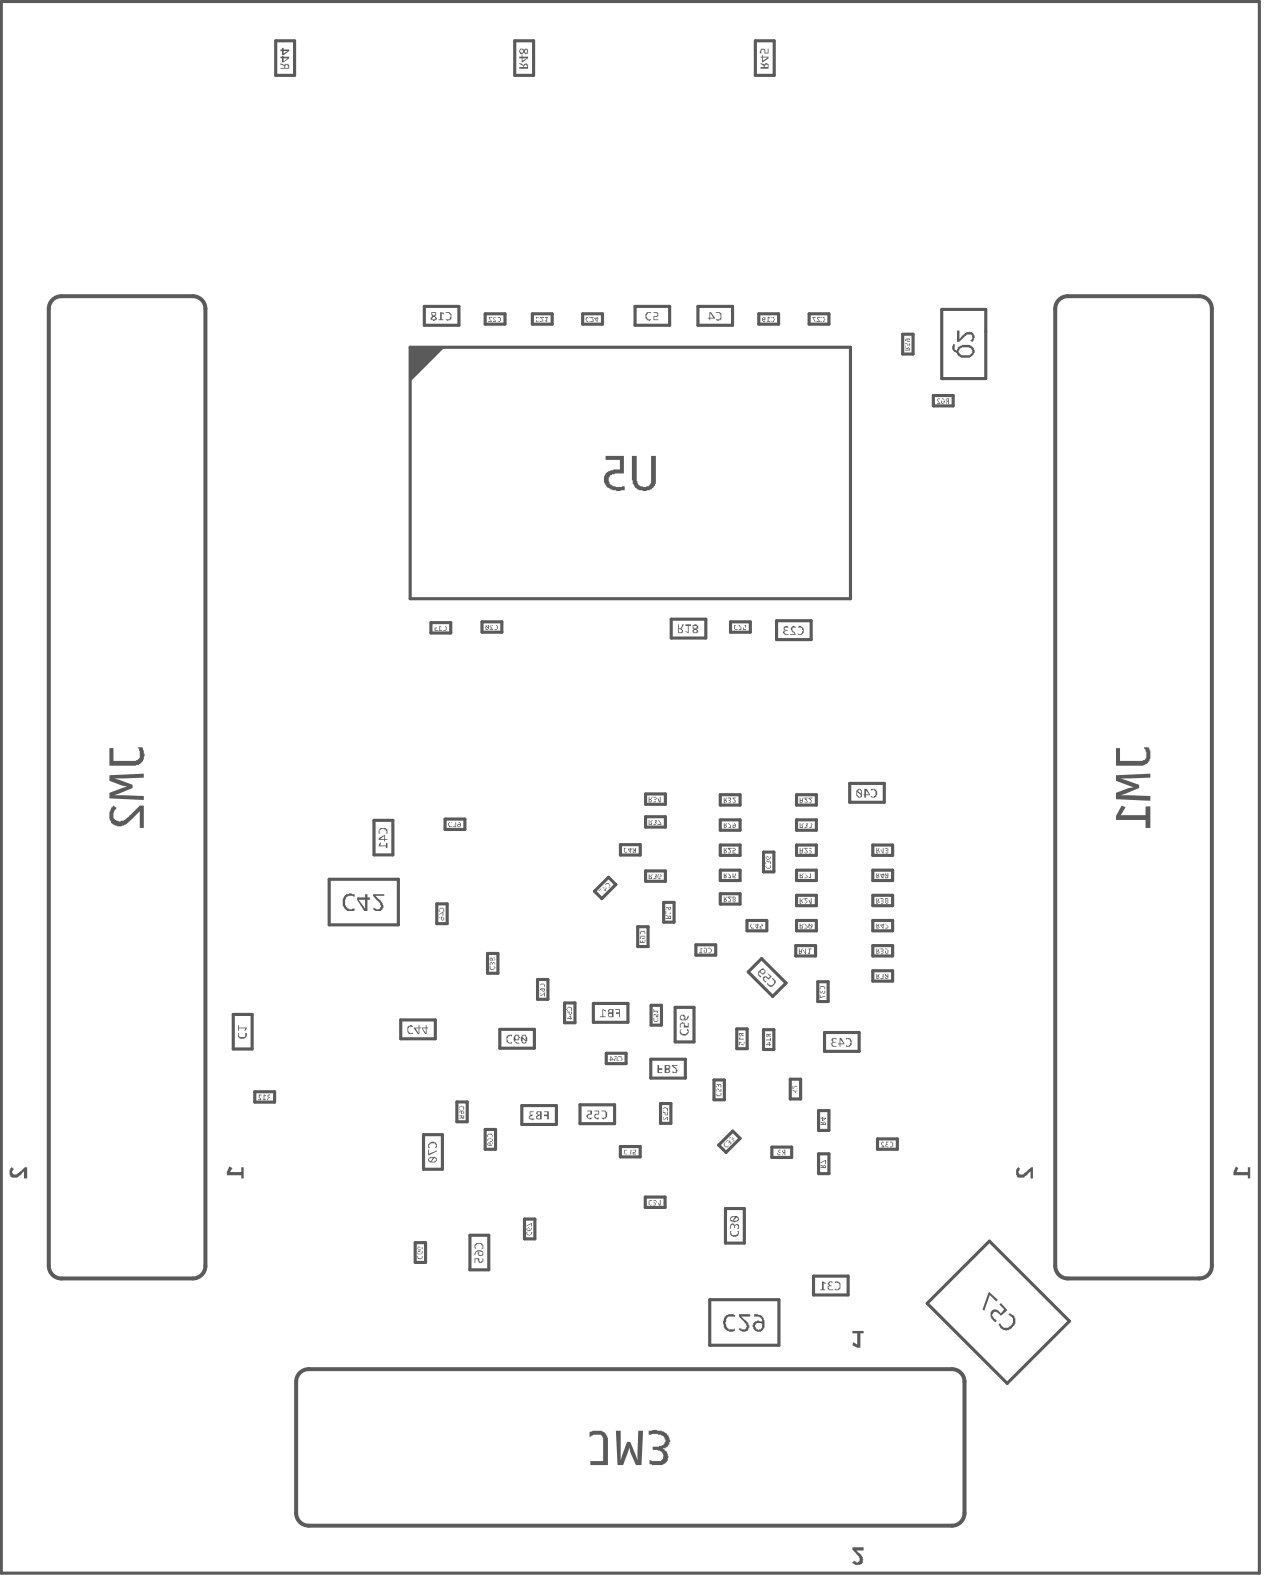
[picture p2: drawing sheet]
<svg xmlns="http://www.w3.org/2000/svg" width="134mm" height="167mm" viewBox="0 0 134 167" stroke-linecap="round" stroke-linejoin="round" font-family="sans-serif">
<path d="M43.4 36.7h3.6l-3.6 3.7z" fill="#5a5a5a"/>
<g fill="none" stroke="#5a5a5a" stroke-width=".33">
<path d="M29.2 4.3h2v3.7h-2zM54.4 4.3h2v3.7h-2zM79.9 4.3h2v3.7h-2zM43.4 36.7h46.6v26.7h-46.6zM44.9 32.4h3.6v2h-3.6zM51.3 33.2h2.1v1.1h-2.1zM56.3 33.2h2.1v1.1h-2.1zM61.6 33.2h2.1v1.1h-2.1zM67.2 32.4h3.6v2h-3.6zM73.8 32.4h3.7v2h-3.7zM80.3 33.2h2.1v1.1h-2.1zM85.6 33.2h2.1v1.1h-2.1z"/>
<path d="M95.5 35.4h1.1v2.1h-1.1zM99.6 32.7h4.7v7.4h-4.7zM98.7 41.9h2.1v1h-2.1zM45.6 65.9h2.1v1.1h-2.1zM51 65.8h2.1v1.1h-2.1zM71 65.5h3.7v2h-3.7zM77.3 65.8h2.1v1.1h-2.1zM82.1 65.7h3.7v2h-3.7zM34.8 93h7.3v4.9h-7.3zM39.6 86.8h2v3.7h-2zM46.2 95.6h1.1v2.1h-1.1zM47.1 86.7h2.1v1.1h-2.1z"/>
<path d="M62.9 94.3l1.5-1.5 .7 .8-1.4 1.5zM65.6 89.4h2.1v1.1h-2.1zM67.5 98.1h1.1v2.1h-1.1zM68.3 84h2.1v1.1h-2.1zM68.3 86.4h2.1v1.1h-2.1zM68.3 92.2h2.1v1.1h-2.1zM70.2 95.5h1.1v2.1h-1.1zM73.6 100h2.1v1.1h-2.1zM76.2 89.4h2.1v1.1h-2.1zM76.2 92.1h2.1v1.1h-2.1zM76.2 86.8h2.1v1h-2.1zM76.2 84.1h2.1v1.1h-2.1z"/>
<path d="M76.2 94.6h2.1v1.1h-2.1zM79 97.4h2.1v1.1h-2.1zM80.8 90.2h1.1v2.1h-1.1zM84.3 89.4h2.1v1.1h-2.1zM84.3 97.4h2.1v1.1h-2.1zM84.3 92.1h2.1v1.1h-2.1zM84.3 94.7h2.1v1.1h-2.1zM84.3 84.1h2.1v1.1h-2.1zM84.3 86.8h2.1v1h-2.1zM89.9 82.9h3.6v2h-3.6zM92.3 89.4h2.1v1.1h-2.1zM92.3 92.1h2.1v1.1h-2.1z"/>
<path d="M92.3 94.7h2.1v1.1h-2.1zM92.3 97.4h2.1v1.1h-2.1zM24.7 107.3h2v3.7h-2zM27 115.5h2v1.1h-2zM42.4 107.9h3.6v2h-3.6zM48.3 116.6h1.1v2.1h-1.1zM51.3 119.5h1.1v2.1h-1.1zM51.6 100.9h1.1v2.1h-1.1zM52.9 108.9h3.6v2h-3.6zM55.2 117h3.7v2h-3.7zM56.9 103.6h1.1v2.1h-1.1zM59.7 106.1h1.1v2.1h-1.1z"/>
<path d="M61.4 116.9h3.6v2h-3.6zM62.8 106.2h3.6v2h-3.6zM64.1 111.4h2.1v1.1h-2.1zM68.8 112.1h3.7v2h-3.7zM68.9 106.4h1.1v2.1h-1.1zM69.9 116.8h1.1v2.1h-1.1zM71.4 106.6h2v3.6h-2zM75.5 114.3h1.1v2.1h-1.1zM77.9 108.9h1.1v2.1h-1.1zM80.6 101.4l2.5 2.6-1.4 1.4-2.6-2.6zM80.8 109h1.1v2h-1.1zM83.6 114.2h1.1v2.1h-1.1z"/>
<path d="M84.2 100.1h2.1v1.1h-2.1zM86.5 103.9h1.1v2.1h-1.1zM86.6 117.5h1.1v2.1h-1.1zM87.2 109.3h3.7v1.9h-3.7zM92.3 100.1h2.1v1.1h-2.1zM92.3 102.7h2.1v1.1h-2.1zM43.9 131.5h1.1v2.1h-1.1zM44.8 120.1h2v3.6h-2zM49.7 130.7h2v3.7h-2zM55.5 129h1.1v2.1h-1.1zM65.6 121.3h2.1v1.1h-2.1zM68.3 126.7h2.1v1.1h-2.1z"/>
<path d="M75.1 137.5h7.3v4.8h-7.3zM76 121.2l1.5-1.5 .8 .8-1.5 1.4zM76.7 127.9h2v3.6h-2zM81.6 121.4h2.1v1.1h-2.1zM86.1 135h3.6v2h-3.6zM86.6 122.1h1.1v2.1h-1.1zM92.8 120.5h2.1v1.1h-2.1zM98.1 137.9l6.6-6.6 8.4 8.5-6.6 6.6z"/>
</g>
<path d="M5.2 32.7v101.2M6.5 31.3h13.9M21.7 32.7v101.2M111.6 32.7v101.2M113 31.3h13.9M128.2 32.7v101.2M6.5 135.3h13.9M113 135.3h13.9M31.3 146.2v13.9M32.7 144.9h68M102 146.2v13.9M32.7 161.4h68" fill="none" stroke="#5a5a5a" stroke-width=".42"/>
<g fill="#5a5a5a">
<path d="M105.6 140.2l.2-.2 .2 .3a.66 .66 0 0 0 1.1-.3v-.1a.45 .45 0 0 0-.2-.6v-.1l-.3-.1 .2-.1a.86 .86 0 0 1 .6 .7 .86 .86 0 0 1-.5 .9l-.2 .1a.86 .86 0 0 1-1-.4z"/>
<path d="M104.9 138.7a.53 .53 0 0 1 .8 .1l.2 .2 .3-.5-.5-.5 .2-.1 .7 .7-.7 .6-.4-.2a.26 .26 0 0 0-.2-.2 .26 .26 0 0 0-.3 .3v.3l.5 .3-.2 .2-.1-.1a.89 .89 0 0 1-.4-1z"/>
<path d="M104.6 136.7l.9 .8-.1 .2-.7-.7-.6 1.7-.2-.2z"/>
<path d="M36.4 94.8l.2-.2h.2l.1-.1 .6 .1v.3h-.2v-.1a.63 .63 0 0 0-.8 .7v.3h.1a.3 .3 0 0 0 .3 .3v.1h.3l.1-.1h.2v.2a.85 .85 0 0 1-1.2-.7v-.5z"/>
<path d="M39.5 94.6h1.1v.2h-.9l.4 .4a.86 .86 0 0 1 .4 1h-.1a.43 .43 0 0 1-.6 .2l-.3-.2 .1-.1a.34 .34 0 0 0 .5 .1 .34 .34 0 0 0 .1-.5v-.2l-.7-.7z"/>
<path d="M76.6 139.3l.2-.1a.63 .63 0 0 1 .7-.1h.2v.3l-.2-.1a.51 .51 0 0 0-.7 .6h-.1l.1 .3a.57 .57 0 0 0 .9 .4v.2l-.2 .1a.55 .55 0 0 1-.6-.2l-.3-.2v-.3l-.1-.1z"/>
<path d="M78.2 139.1h1.1v.2h-.9l.4 .4a.79 .79 0 0 1 .4 1h-.1a.48 .48 0 0 1-.7 .1l-.2-.1v-.2a.52 .52 0 0 0 .7 .1v-.2h.1l-.1-.3-.7-.8z"/>
<path d="M80.4 5.2h.1a.24 .24 0 0 1 .3 0 .24 .24 0 0 1 .2 .2v.2h.2v-.4h.1v.5h-.4v-.3a.18 .18 0 0 0-.3-.2 .18 .18 0 0 0-.1 .3v.2l-.1-.1z"/>
<path d="M72.5 66.1h.6v.1h-.3v.8l-.3-.2v-.1l.3 .2v-.7h-.3z"/>
<path d="M57.5 117.6h.6v.8h-.2v-.3h-.4v-.2h.4v-.2h-.4z"/>
<path d="M56 117.6h.4v.1h-.3v.2h.3v.1l-.4 .2a.38 .38 0 0 0 .5 .2h-.1a.34 .34 0 0 1-.5-.2l.2-.2-.1-.2h-.1h.1z"/>
<path d="M69.5 112.7h.2v.3h.4v.2h-.4v.3h.4h-.6z"/>
<path d="M71.1 112.7h.6v.1h-.5l.5 .4-.1 .3h-.4h-.1l.1-.1v.1a.19 .19 0 0 0 .3-.1 .19 .19 0 0 0-.1-.3z"/>
<path d="M65.1 106.8h.5v.8h-.1v-.3h-.3v-.2h.3v-.2h-.4z"/>
<path d="M63.7 106.8l.4 .2-.3-.1v.6h.3v.1h-.6v-.1h.2z"/>
<path d="M45.3 121.1h.1a.44 .44 0 0 1 .6-.3 .44 .44 0 0 1 .1 .7v-.2a.35 .35 0 0 0-.5-.3l-.2 .1 .1 .4-.2-.1z"/>
<path d="M45.3 121.7h.1v.4l.8-.4v.1l-.9 .4z"/>
<path d="M50.2 131.7h.1a.44 .44 0 0 1 .6-.2l.1 .1a.38 .38 0 0 1 .1 .5h-.1a.24 .24 0 0 0 0-.2 .24 .24 0 0 0-.1-.2v-.1a.38 .38 0 0 0-.5 .2h-.1l.1 .2-.1 .1-.1-.1z"/>
<path d="M50.2 133.1h.5v.4l.1 .1 .2-.2v-.3a.24 .24 0 0 1 .1 .3 .24 .24 0 0 1-.1 .2h-.3l-.1-.2h-.1v-.2h-.2v.4h-.1z"/>
<path d="M53.7 109.6l.5-.1v.2l-.2-.1-.3 .1v.1v.3v.1a.24 .24 0 0 0 .2 .1 .24 .24 0 0 0 .3-.1v.2h-.2a.34 .34 0 0 1-.4-.4v-.3z"/>
<path d="M81.1 104.1l.1-.1a.36 .36 0 0 0 .5 .2 .36 .36 0 0 0 .2-.5l-.3-.1 .2-.1 .1 .2a.27 .27 0 0 1 .2 .2 .27 .27 0 0 1-.2 .3h-.1a.31 .31 0 0 1-.3 .2 .31 .31 0 0 1-.3-.2z"/>
<path d="M80.7 103.4l.1-.1h.3l.2 .2 .2-.2-.3-.3 .4 .3-.3 .4-.2-.2a.18 .18 0 0 0-.2 0 .18 .18 0 0 0 0 .2l.1 .1v.2l-.3-.3z"/>
<path d="M71.9 109l.2-.1a.3 .3 0 0 0-.1 .3 .3 .3 0 0 0 .2 .2h.2a.3 .3 0 0 0 .4-.3h-.1v-.2a.31 .31 0 0 1 .1 .3 .31 .31 0 0 1-.2 .3v.1h-.3a.42 .42 0 0 1-.4-.5z"/>
<path d="M72 108.2h.2v-.1l.2 .1v.3l.1 .1h.3v-.4v.5h-.5v-.4h-.2l-.1 .1v.3h-.1z"/>
<path d="M63.6 117.5a.38 .38 0 0 1 .5 .2l.1 .1a.45 .45 0 0 1-.2 .6h-.1h-.3v-.1h.3a.43 .43 0 0 0 .2-.6l-.1-.1h-.4v.1z"/>
<path d="M62.9 117.5h.5v.4h-.3a.18 .18 0 0 0-.1 .3 .18 .18 0 0 0 .2 .1h.2v.1h-.1h-.3a.26 .26 0 0 1-.1-.3 .26 .26 0 0 1 .2-.3h.2v-.2h-.4z"/>
<path d="M62.1 117.5h.5v.4h-.3l-.1 .1v.3h.4v.1h-.2h-.2l-.2-.2a.32 .32 0 0 1 .4-.4v-.2h-.3z"/>
<path d="M43.2 108.6h.1a.24 .24 0 0 1 .2-.1 .24 .24 0 0 1 .2 .1 .34 .34 0 0 0-.4 .1 .34 .34 0 0 0-.1 .3 .32 .32 0 0 0 .4 .3l.1-.1v.2h-.1a.39 .39 0 0 1-.4-.1 .39 .39 0 0 1-.1-.4v-.3z"/>
<path d="M89.5 109.8a.44 .44 0 0 1 .5 .1 .44 .44 0 0 1 .1 .5 .32 .32 0 0 1-.4 .4h-.2v-.2a.34 .34 0 0 0 .5-.3 .34 .34 0 0 0-.5-.3z"/>
<path d="M88 109.9l.1-.1h.4v.2l-.1-.1h-.3a.22 .22 0 0 0 0 .3 .22 .22 0 0 0 .3 0v.1h-.3v.3v.1h.4v.1a.34 .34 0 0 1-.5-.3l-.1-.1 .2-.2h-.1z"/>
<path d="M40.1 87.7l.3-.1a.38 .38 0 0 1 .5 .2h.1v.4h-.2a.34 .34 0 0 0-.1-.5 .34 .34 0 0 0-.5 .2h-.1v.2l.1 .1h-.1z"/>
<path d="M40.2 89.1l.1 .1-.1 .3h.6v-.3h.2v.5h-.2v-.2h-.7z"/>
<path d="M92.1 83.6l.1-.1h.2a.48 .48 0 0 1 .4 .3 .48 .48 0 0 1-.2 .5 .3 .3 0 0 1-.5-.1l.2 .1a.35 .35 0 0 0 .3-.5l-.2-.2h-.1h-.2z"/>
<path d="M88.3 135.7l.2-.1a.34 .34 0 0 1 .4 .4v.2a.32 .32 0 0 1-.4 .3h-.2v-.1a.24 .24 0 0 0 .2 0 .24 .24 0 0 0 .2-.1h.1a.48 .48 0 0 0-.3-.6v.1h-.2z"/>
<path d="M87.5 135.8h.1a.24 .24 0 0 1 .2-.2 .24 .24 0 0 1 .3 .1v.1l-.2-.1a.18 .18 0 0 0-.2 .2 .18 .18 0 0 0 .3 .1v.1h-.3a.25 .25 0 0 0 .1 .3 .25 .25 0 0 0 .3 0v.1a.39 .39 0 0 1-.4 0 .39 .39 0 0 1-.2-.4l.2-.1h-.1z"/>
<path d="M87 135.6l.4 .2h-.1h-.2v.6h.2v.1h-.5v-.1h.2z"/>
<path d="M77.2 130.3h.2l-.1 .2 .2 .2a.38 .38 0 0 0 .5-.2h.1l-.1-.2h.2v.2a.48 .48 0 0 1-.4 .4 .48 .48 0 0 1-.5-.2l-.1-.1z"/>
<path d="M77.3 129.5l.3-.1 .1 .3a.23 .23 0 0 1 .3-.2 .23 .23 0 0 1 .2 .3v.2h-.2l.1-.1-.1-.3-.3 .1v.2v-.1a.18 .18 0 0 0-.3-.2 .18 .18 0 0 0-.1 .2v.2h-.1v-.4z"/>
<path d="M84.4 66.3a.3 .3 0 0 1 .3-.1 .3 .3 0 0 1 .2 .3l.1 .1a.38 .38 0 0 1-.2 .5v.1h-.4v-.2a.24 .24 0 0 0 .3 .1 .24 .24 0 0 0 .1-.3 .3 .3 0 0 0 0-.3 .3 .3 0 0 0-.3-.1z"/>
<path d="M83.7 66.4a.22 .22 0 0 1 .3-.2 .22 .22 0 0 1 .2 .3l-.1-.1a.19 .19 0 0 0-.3 .1 .19 .19 0 0 0 .1 .2l.3 .5h-.6v-.1h.5l-.4-.3z"/>
<path d="M82.9 66.3h.1a.24 .24 0 0 1 .2-.1 .24 .24 0 0 1 .2 .2h-.3l-.1 .1 .1 .2h.2h-.2a.18 .18 0 0 0-.1 .3 .18 .18 0 0 0 .2 .1h.2v.1a.38 .38 0 0 1-.5-.2h-.1v-.2l.3-.1h-.2z"/>
<path d="M47.2 33a.38 .38 0 0 1 .5 .2v.1a.55 .55 0 0 1-.1 .6l-.3 .1-.1-.2a.34 .34 0 0 0 .3 0 .34 .34 0 0 0 .2-.3 .32 .32 0 0 0-.5-.4v.1z"/>
<path d="M46.6 33l.4 .1-.1 .2-.2-.2v.7h.2v.1h-.5v-.1h.2z"/>
<path d="M68.3 33.2l.1-.2h.5v.2a.24 .24 0 0 0-.3-.1 .24 .24 0 0 0-.2 .3v.3l.1 .1h.4l-.2 .2-.1-.1a.32 .32 0 0 1-.3-.4z"/>
<path d="M69.1 33a.34 .34 0 0 1 .5 .3l-.1 .2h-.3v.3h.4v.1h-.5v-.4h.3a.18 .18 0 0 0 .1-.3 .18 .18 0 0 0-.2-.1h-.2z"/>
<path d="M75.7 33a.44 .44 0 0 1 .5 .1 .44 .44 0 0 1 .1 .5l-.1 .3-.2 .1-.3-.1v-.1a.34 .34 0 0 0 .4 0 .34 .34 0 0 0 .1-.3 .35 .35 0 0 0-.5-.4v.1z"/>
<path d="M25.2 109.3h.2a.24 .24 0 0 0-.1 .3 .24 .24 0 0 0 .2 .1 .3 .3 0 0 0 .4 0 .3 .3 0 0 0 0-.4h.2v.2a.46 .46 0 0 1-.6 .4 .32 .32 0 0 1-.3-.4z"/>
<path d="M25.2 108.5h.1v.2h.8v.1l-.2 .3v-.3h-.6v.3h-.1z"/>
<path d="M93.6 89.7h.3l.1 .1v.2h-.1l.1 .2-.1 .1-.3-.1h.3v-.1h-.2v-.1h.2v-.2h-.3z"/>
<path d="M93.6 97.7h.4h-.3l.1 .2a.18 .18 0 0 1 .2 .2 .18 .18 0 0 1-.3 .2l-.1-.1h.3v-.2z"/>
<path d="M85.5 100.4h.4h-.2v.6l-.3-.1 .1-.1 .1 .1v-.5z"/>
<path d="M93.1 100.4h.3h.1v.2h-.1l.1 .3-.1 .1h-.2v-.1h.2v-.2h-.2v-.1l.3-.1-.1-.1h-.3z"/>
<path d="M93.1 95h.3l.1 .1v.2h-.1l.1 .2-.1 .1h-.2v-.1h.2v-.1h-.2v-.1l.3-.1-.1-.1h-.3z"/>
<path d="M69.1 86.8h.4v.2h-.1l.1 .2-.1 .1h-.3v-.1h.3l-.2-.2 .2-.2z"/>
<path d="M69.6 86.8h.1l.3 .5h-.5v-.1h.4z"/>
<path d="M69.1 92.5h.4v.3h-.1l.1 .1-.1 .1h-.3v-.1h.3l-.2-.1 .2-.2z"/>
<path d="M69.1 84.3h.2a.17 .17 0 0 1 .2 .2 .17 .17 0 0 1-.2 .1l.2 .1-.2 .2h-.2v-.1l.3-.1v-.1h-.2h.2v-.2h-.3z"/>
<path d="M85.1 87.1h.3v.3h-.1l.1 .1-.1 .1h-.2v-.1h.2l-.1-.1 .1-.2z"/>
<path d="M85.6 87.1h.3v.1l-.1 .2h.1v.2h-.3v-.1h.2v-.1h-.2l.3-.1-.1-.2z"/>
<path d="M77 84.4h.3v.2h-.1l.1 .3-.1 .1h-.1v-.1h.1v-.2h-.1v-.1h.2l-.1-.1h-.2z"/>
<path d="M77.5 84.4h.3v.1h-.2l.2 .3a.17 .17 0 0 1-.1 .2 .17 .17 0 0 1-.2-.2l.2 .1v-.2z"/>
<path d="M93.1 103.1h.4v.2h-.1h.1a.19 .19 0 0 1-.1 .3 .19 .19 0 0 1-.3-.1h.3v-.2h-.2l.2-.1v-.1z"/>
<path d="M77 87.1h.4h-.3l.2 .3v.2h-.2l-.1-.1h.2v-.1z"/>
<path d="M77 94.9h.4v.1h-.3h.1a.24 .24 0 0 1 .1 .3 .24 .24 0 0 1-.2 .2l-.1-.1 .1-.1v.1h.1v-.3z"/>
<path d="M77 92.4h.4h-.3l.2 .3v.2h-.2l-.1-.1h.2v-.1z"/>
<path d="M77 89.7h.4v.1h-.2a.33 .33 0 0 1 0 .5l-.2-.1 .1-.1v.1h.1v-.2z"/>
<path d="M77.5 89.7h.2a.18 .18 0 0 1 .1 .2 .18 .18 0 0 1-.2 .2v.1h.2v.1h-.3v-.3h.2v-.2h-.2z"/>
<path d="M85.1 95h.3v.1h-.2l.2 .3-.1 .2-.2-.1h.2v-.1l-.1-.1z"/>
<path d="M85.1 89.7h.3v.1h-.2l.2 .3a.17 .17 0 0 1-.1 .2 .17 .17 0 0 1-.2-.2l.2 .1v-.1z"/>
<path d="M85.6 89.7h.3v.2l-.1 .1 .1 .1-.1 .2h-.2v-.1h.2v-.1h-.2v-.1h.3v-.2h-.3z"/>
<path d="M85.1 84.4h.3v.1h-.2l.1 .1 .1 .2a.17 .17 0 0 1-.1 .2 .17 .17 0 0 1-.2-.2l.2 .1v-.2l-.1-.1z"/>
<path d="M85.5 84.4h.4v.1h-.3l.2 .1a.24 .24 0 0 1 .1 .2 .24 .24 0 0 1-.2 .2l-.2-.1 .1-.1v.1h.2v-.3z"/>
<path d="M85.1 92.4h.3h-.2l.1 .2a.18 .18 0 0 1 .1 .2 .18 .18 0 0 1-.2 .1l-.1-.1h.2v-.1z"/>
<path d="M85.6 92.4h.3h-.1v.5l-.3-.1h.1h.1v-.4z"/>
<path d="M85.1 97.7h.3h-.2l.1 .2a.18 .18 0 0 1 .1 .2 .18 .18 0 0 1-.2 .2l-.1-.1h.2v-.2z"/>
<path d="M70.4 96.4h.1v.2h.5l-.1 .1h-.1l.1-.1h-.4v.1h-.1z"/>
<path d="M78.2 109.7l.1 .1-.1 .1h.5v-.1v.4v-.2h-.5z"/>
<path d="M78.2 110.2h.2l.1 .3h.2v-.3h.1v.2h-.1v.2h-.3v-.3h-.2v.3z"/>
<path d="M81.1 109.8l-.1 .2h.5v-.2v.4v-.1h-.5z"/>
<path d="M27.9 115.8l.2 .1v.1l-.1-.1v.4h.1v.1h-.3l.1-.1z"/>
<path d="M27.4 115.8h.2v.2v-.1h-.1v.3l.1 .2h-.3v-.1h.2l-.1-.1z"/>
<path d="M86.8 123l.6-.3v.5h-.1v-.4l-.5 .3z"/>
<path d="M82.3 121.7h.3h-.2v.2h.2v.1h-.3v.2h.3h-.3h-.1v-.2h.2z"/>
<path d="M83.8 114.9h.1v.2l.2-.2h.2v.3l-.1-.1h.1v-.1h-.2l-.3 .2z"/>
<path d="M51.5 120h.3a.22 .22 0 0 1 .2 0 .22 .22 0 0 1 .1 .3h-.1h.1a.24 .24 0 0 0-.2-.2 .24 .24 0 0 0-.3 0v.2h-.1z"/>
<path d="M48.6 117.1l.3-.1v.1h.2v.3h-.1v-.1a.22 .22 0 0 0-.2-.2 .22 .22 0 0 0-.2 .2l.1 .1h-.1z"/>
<path d="M55.7 130.4h.1a.23 .23 0 0 0 .2 .3 .23 .23 0 0 0 .2-.3h.1v.2l-.3 .1v.1l-.3-.2z"/>
<path d="M55.7 129.7l.6-.3v.4h-.1v-.3l-.5 .3z"/>
<path d="M44.1 133l.2-.1-.1 .1a.24 .24 0 0 0 .2 .1 .24 .24 0 0 0 .2 0v-.2h.1v.2a.38 .38 0 0 1-.5 .1z"/>
<path d="M65.4 111.8h.3v.1a.24 .24 0 0 1 .1 .2 .24 .24 0 0 1-.2 .2h-.2v-.1l.2 .1a.23 .23 0 0 0 .1-.3 .23 .23 0 0 0-.3-.1z"/>
<path d="M67.7 98.6l.2-.1a.22 .22 0 0 1 .3 .1 .22 .22 0 0 1 0 .2h-.1h.1a.24 .24 0 0 0-.2-.2 .24 .24 0 0 0-.2 .1v.1h-.1z"/>
<path d="M67.7 99.5h.1v.2h.1v-.2h.1v.2h.2v-.3h.1l-.1 .4h-.3v-.1v.1h-.2z"/>
<path d="M57.1 104.2h.1a.24 .24 0 0 1 .3-.1 .24 .24 0 0 1 .1 .2l-.1 .1a.19 .19 0 0 0 0-.2 .19 .19 0 0 0-.3 0h-.1v.2h.1h-.1z"/>
<path d="M57.1 105l.1 .1-.1 .2h.3l.2-.3v.4h-.1v-.3l-.1 .2h-.3z"/>
<path d="M74.9 100.3h.1a.32 .32 0 0 1 .3 .4l-.2 .2-.2-.1h.1a.23 .23 0 0 0 .2-.3 .23 .23 0 0 0-.3-.1z"/>
<path d="M74.1 100.3l.2 .1h-.1v.4l.1 .1h-.4v-.1h.2z"/>
<path d="M60 106.6a.31 .31 0 0 1 .4 0 .31 .31 0 0 1 .1 .4h-.1a.23 .23 0 0 0-.1-.4 .23 .23 0 0 0-.3 .3l.1 .1-.2-.1z"/>
<path d="M60 107h.2v.3h.2v-.3h.1v.2a.18 .18 0 0 1-.2 .2 .18 .18 0 0 1-.1-.3h-.2v.3z"/>
<path d="M75.7 115.7h.2h-.1a.24 .24 0 0 0 .2 .2 .24 .24 0 0 0 .2-.1v-.1h.1v.1a.38 .38 0 0 1-.5 .2z"/>
<path d="M75.9 115.1l.2 .1v.2h.1v-.2h.1v.3h-.2l-.1-.3-.3 .3z"/>
<path d="M75.8 114.7h.3v.1v-.1h.1l.1 .1v.3h-.1v-.3h-.1v.2h-.1v-.2h-.2v.3h-.1z"/>
<path d="M70.1 117.3l.1-.1h.3v.1h.1v.3v-.2a.21 .21 0 0 0-.3-.2 .21 .21 0 0 0-.1 .4h-.1z"/>
<path d="M70.1 117.7h.3v.2h.2v-.2v.2l-.2 .1-.1-.2h-.2v.2z"/>
<path d="M70.1 118.2h.1l-.1 .1 .1 .1 .4-.2v.3v-.2l-.4 .2-.1-.1z"/>
<path d="M69.1 107.7h.1v.2h-.1h.1v.2h.3v-.2h.1l-.1-.2a.24 .24 0 0 1 .1 .3 .24 .24 0 0 1-.2 .1h-.3z"/>
<path d="M69.1 107.4l.3-.1 .1 .2v-.2h.1v.3h-.2v-.2h-.2l-.1 .1 .1 .1h-.1z"/>
<path d="M69.1 106.8h.1v.2h.4l-.1 .2v-.1v-.1h-.3l-.1 .1z"/>
<path d="M66 89.7h.3v.1l-.1-.1a.24 .24 0 0 0-.1 .2 .24 .24 0 0 0 .1 .2h.1v.1h-.1a.38 .38 0 0 1-.2-.5z"/>
<path d="M64.1 93.5l.1-.1a.3 .3 0 0 1 .3 .2 .3 .3 0 0 1 0 .3h-.2a.23 .23 0 0 0 .2-.3 .23 .23 0 0 0-.4-.1v.2l-.1-.1z"/>
<path d="M63.3 94.3l.3-.3-.2 .3 .5 .1z"/>
<path d="M46.5 96.1h.1a.24 .24 0 0 1 .2 0 .24 .24 0 0 1 .2 .2v.2l-.1-.1a.19 .19 0 0 0-.1-.3 .19 .19 0 0 0-.2 .1h-.1l.1 .3h-.1l-.1-.1z"/>
<path d="M79.3 97.8l.1-.1h.4v.1l-.2-.1a.23 .23 0 0 0-.2 .4 .23 .23 0 0 0 .4 .1v.1h-.4z"/>
<path d="M80.4 97.7h.2l.1 .1v.2l-.3 .1 .2 .2h-.2v-.3l.2-.1-.1-.2z"/>
<path d="M47.4 87.1l.1-.1h.3v.1a.22 .22 0 0 0-.2 0 .22 .22 0 0 0-.1 .3h.1h.2v.1h-.3z"/>
<path d="M47.9 87h.4v.3h-.1l.1 .2h-.4v-.1h.3l-.2-.1h.2v-.3z"/>
<path d="M51.8 102.2h.1a.23 .23 0 0 0 .1 .4 .23 .23 0 0 0 .3-.3l-.1-.1a.17 .17 0 0 1 .2 .2 .17 .17 0 0 1-.2 .2 .24 .24 0 0 1-.3 0 .24 .24 0 0 1-.1-.2z"/>
<path d="M51.8 101.9l.1-.1h.2v.1l.2-.1 .1 .3h-.1v-.2h-.2v.2v-.2h-.2v.2h-.1z"/>
<path d="M86.8 104.3a.34 .34 0 0 1 .5 .3l-.1 .1a.22 .22 0 0 0-.2-.3 .22 .22 0 0 0-.2 .2l.1 .1h-.2z"/>
<path d="M86.7 104.8h.1v.2h.2v-.2v.3h.2v-.3h.1v.3l-.3 .1v-.2l-.2 .1z"/>
<path d="M86.7 105.3h.1v.2l.5-.2v.1l-.6 .2z"/>
<path d="M81 91.7l.1-.1-.1 .1a.24 .24 0 0 0 .2 .1 .24 .24 0 0 0 .3-.1v-.1v.1a.27 .27 0 0 1-.2 .2 .27 .27 0 0 1-.3-.2z"/>
<path d="M81 91.1l.3 .1 .2-.1v.1v.2v-.2l-.2 .1-.1-.1h-.2v.2z"/>
<path d="M66 121.7h.1h.2h-.1a.27 .27 0 0 0-.1 .2 .27 .27 0 0 0 .1 .3l.1-.1v.1h-.2l-.1-.1z"/>
<path d="M66.5 121.7h.3l-.1 .2h.1v.3h-.3v-.1l.2 .1v-.3h-.2l.3-.1-.1-.1z"/>
<path d="M66.9 121.7h.4v.2l-.3 .1v.1h.3v.1h-.4v-.3h.3v-.2h-.1h-.2z"/>
<path d="M68.6 127.1l.1-.1h.3v.1a.22 .22 0 0 0-.3 .1 .22 .22 0 0 0 .2 .3l.1-.1v.1a.25 .25 0 0 1-.3-.1 .25 .25 0 0 1-.1-.3z"/>
<path d="M69.1 127h.3l.1 .1v.1h-.2l.1 .1-.1 .3h-.2v-.1h.2v-.2h-.2v-.1h.3v-.1h-.3z"/>
<path d="M76.6 121l.2-.1a.21 .21 0 0 0-.2 .3 .21 .21 0 0 0 .4 0l.1-.1v.1a.24 .24 0 0 1-.2 .2 .24 .24 0 0 1-.3-.1v-.1z"/>
<path d="M76.8 120.7a.24 .24 0 0 1 .2-.1 .24 .24 0 0 1 .2 .2l.2 .1-.2 .2 .1-.2-.2 .1 .1-.3-.1-.1-.2 .2z"/>
<path d="M77.2 120.4v-.1h.3l.1 .1-.1 .1h.2v.2l-.2 .1 .2-.2h-.3v-.1h.1l-.1-.2-.2 .2z"/>
<path d="M94.1 120.8h.2a.38 .38 0 0 1 .2 .5l-.1 .1h-.3v-.1h.3v-.4h-.3z"/>
<path d="M93.7 120.8h.3v.1l-.3 .1 .2 .1h-.2v.2h.3v.1l-.4-.1v-.2h.2h-.1z"/>
<path d="M93.2 120.9l.1-.1 .2 .1v.1v-.1h-.2v.2l.2 .3h-.3v-.1h.3l-.3-.2z"/>
<path d="M86.9 33.5h.3v.2a.25 .25 0 0 1 0 .3 .25 .25 0 0 1-.3 0 .21 .21 0 0 0 .3-.1 .21 .21 0 0 0 0-.2 .21 .21 0 0 0-.3-.1z"/>
<path d="M86.4 33.5h.4v.1h-.2v-.1l-.1 .1v.2l.3 .2h-.4h.3l-.3-.2z"/>
<path d="M85.9 33.5h.4v.1h-.3l.3 .4h-.1z"/>
<path d="M77.7 66.1h.3v.1l-.1-.1a.24 .24 0 0 0-.2 .2 .24 .24 0 0 0 .1 .3h.2v.1h-.2a.38 .38 0 0 1-.1-.6z"/>
<path d="M78.1 66.1h.4h-.3l.1 .2a.19 .19 0 0 1 .1 .3 .19 .19 0 0 1-.2 .1l-.1-.1h.2v-.3z"/>
<path d="M78.6 66.1h.3v.3h-.2v.2h.2v.1h-.3v-.3h.2v-.2z"/>
<path d="M62 33.5h.4v.1a.21 .21 0 0 0-.3 .1 .21 .21 0 0 0 0 .2 .21 .21 0 0 0 .3 .1h-.4v-.1h-.1z"/>
<path d="M62.4 33.5h.4v.1h-.3l.3 .2a.19 .19 0 0 1-.1 .2 .19 .19 0 0 1-.3 0h.2h.1v-.2z"/>
<path d="M52.6 33.5h.2a.27 .27 0 0 1 .2 .4 .27 .27 0 0 1-.4 .1h.1h.2v-.4h-.2v-.1l-.1 .1z"/>
<path d="M52.1 33.6l.1-.1h.3v.1l-.1-.1a.17 .17 0 0 0-.2 .2 .17 .17 0 0 0 .2 .2l.1 .1h-.4h.3l-.2-.1z"/>
<path d="M51.7 33.5h.4v.1h-.2v-.1l-.1 .1v.2l.3 .2h-.5h.4l-.3-.2z"/>
<path d="M56.7 33.5h.3v.1a.21 .21 0 0 0-.2 .1 .21 .21 0 0 0 0 .2 .21 .21 0 0 0 .2 .1 .21 .21 0 0 1-.3 0 .21 .21 0 0 1 0-.3z"/>
<path d="M57.1 33.5h.4v.1h-.3l.3 .2a.19 .19 0 0 1-.1 .2 .19 .19 0 0 1-.3 0h.3v-.2z"/>
<path d="M57.6 33.5h.4l-.1 .1v.4h-.3v-.1l.2 .1v-.4h-.2z"/>
<path d="M52.3 66.1v.1a.21 .21 0 0 1 .3 0 .21 .21 0 0 1 0 .3v.2h-.3v-.1a.19 .19 0 0 0 .3-.1 .19 .19 0 0 0-.1-.3v-.1z"/>
<path d="M51.8 66.2l.1-.1h.2v.1v-.1l-.2 .1 .2 .5h-.3v-.1h.3l-.2-.1z"/>
<path d="M81.5 33.5h.4v.2a.25 .25 0 0 1-.1 .3 .25 .25 0 0 1-.3 0 .21 .21 0 0 0 .3-.1 .21 .21 0 0 0 0-.2 .21 .21 0 0 0-.3-.1z"/>
<path d="M81.2 33.5l.3 .1-.1 .1-.1-.1v.4h.2h-.4h.1z"/>
<path d="M46.9 66.2v.1v-.1h.2a.27 .27 0 0 1 .1 .4 .27 .27 0 0 1-.3 .1 .19 .19 0 0 0 .3-.1 .19 .19 0 0 0-.1-.3v-.1z"/>
<path d="M46.5 66.2l.2 .1h-.1v.4h.1h-.3h.1z"/>
<path d="M46 66.2h.2v.3h-.1v.2h.2a.19 .19 0 0 1-.2 0 .19 .19 0 0 1-.1-.2 .19 .19 0 0 1 .2-.1v-.2z"/>
<path d="M90.2 140.8h1.1v.3h-.3v1.5h-.3l-.5-.3v-.3l.5 .3v-1.2h-.5z"/>
<path d="M90.2 163.7h1.1v.4h-.7l.3 .3a.79 .79 0 0 1 .3 1.1l-.4 .1a.55 .55 0 0 1-.6-.2v-.1l.1-.1h.3v.1a.35 .35 0 0 0 .3-.5h-.1v-.1l-.6-.7z"/>
<path d="M62.4 151.6a2.07 2.07 0 0 1 1.4-.1l.3 .1v.3a.55 .55 0 0 1 .2 .6v2.5h-1.9v-.4h1.4v-2.5h-.1a.57 .57 0 0 0-.7-.3h-.2l-.4 .3z"/>
<path d="M65.2 151.4h.5v3.1l.6-1.9h.4l.7 1.9 .1-3.1h.5l-.1 3.6h-.6l-.6-1.3-.1-.5-.7 1.8h-.6z"/>
<path d="M68.6 151.4h.4v-.1h.5v.1a.86 .86 0 0 1 .9 .2 .98 .98 0 0 1 .4 1.2h-.1l-.1 .3-.5 .2h.1l.1 .2a.48 .48 0 0 1 .3 .6h.1l-.1 .3a1 1 0 0 1-1.2 .6l-.7-.1v-.4l.6 .1a.6 .6 0 0 0 .8-.4l.1-.2h-.1v-.2l-.1-.2-.5-.2h-.5v-.3h.7l.1-.1a.43 .43 0 0 0 .5-.4h.1l-.1-.5a.68 .68 0 0 0-.7-.3l-.1-.1-.9 .1z"/>
<path d="M24.3 123.4l.3 .2-.3 .4h1.2v-.5h.3v1.2h-.3v-.3h-1.5v-.4z"/>
<path d="M11.6 79.2h.4v1.3h2.1a.63 .63 0 0 0 .7-.8l-.1-.5-.2-.1h.5l.2 .3v.3h.1l-.1 .5a1.08 1.08 0 0 1-.6 .7l-.2 .1h-2.8z"/>
<path d="M11.6 82l3.6-.1v.4l-3.1 .1 1.9 .6v.4l-1.9 .7 3.1 .1v.4l-3.6-.1v-.6l1.8-.7-.5-.1-1.3-.5z"/>
<path d="M11.7 85.5l.3-.3 .3 .3v.1a.98 .98 0 0 0-.2 1.1l.2 .1a1.26 1.26 0 0 0 1.1-.2l1.4-1.4h.4v2.4h-.4v-1.8l-.9 1a2.07 2.07 0 0 1-1.2 .6h-.3h-.1a.81 .81 0 0 1-.6-.6l-.1-.1v-.8z"/>
<path d="M1.1 123.6l.2-.1 .1 .2v.2h-.1a.35 .35 0 0 0 .5 .4v-.1l.2-.1 .6-.6h.3v1.2h-.4v-.8l-.5 .5a.72 .72 0 0 1-.8 .1l-.2-.1v-.6h.1z"/>
<path d="M130.7 123.4l.3 .2-.2 .4h1.2v-.5h.2v1.2h-.2v-.3h-1.5v-.4z"/>
<path d="M118 79.2h.5v1.3h2.3a.73 .73 0 0 0 .4-1.1l-.2-.3h.5a1.8 1.8 0 0 1-.1 1.7l-.5 .2h-2.9z"/>
<path d="M118 82l3.7-.1v.4l-3.1 .1 1.9 .6v.4l-1.9 .7 3.1 .1v.5l-3.7-.1v-.7l1.4-.5 .5-.1-1.9-.7z"/>
<path d="M118.6 85.2l.5 .2-.5 .9h2.6v-1h.5v2.3h-.5v-.8h-3.2v-.5z"/>
<path d="M107.7 123.5l.2 .2a.34 .34 0 0 0 0 .6h.3l.1-.2 .3-.1 .5-.5h.2v1.2h-.3v-.8l-.3 .5h-.3a.44 .44 0 0 1-.6 .2h-.1a.97 .97 0 0 1 0-1.1z"/>
<path d="M66.8 48.2h.5v2.7h.1a.44 .44 0 0 0 .5 .5 .64 .64 0 0 0 1-.5v-2.7h.5v2.5a1.01 1.01 0 0 1-1 1.2v.1h-.4l-.1-.1a.89 .89 0 0 1-.9-.7h-.1v-.3l-.1-.1z"/>
<path d="M64.1 48.2h1.9v1.9h-.9l-.1 .1a.59 .59 0 0 0-.6 .3 .59 .59 0 0 0 .1 .6 1.13 1.13 0 0 0 1.1 .4l.5-.1v.5h-.4v.1a2.08 2.08 0 0 1-1.6-.6 1.01 1.01 0 0 1 .4-1.6l.4-.1h.7v-1h-1.5z"/>
<path d="M95.7 36.3h.3l.1 .3h.1v-.3v.3h-.2l-.1-.3v.1h-.2v.2h.1l-.1 .1z"/>
<path d="M101.2 35h.3v.9l.6-.7 .4-.1h.2a.3 .3 0 0 1 .3 .4h.1v.2l-.2 .5-.2-.1v-.1a.38 .38 0 0 0 .1-.5l-.1-.1a.38 .38 0 0 0-.5 .2l-.7 .6h-.3z"/>
<path d="M99.1 42.2h.1h.3h-.3v.2h.1l.2 .3h-.4h.3l-.3-.3z"/>
<path d="M37.9 95.2h.7v.9zM37.8 95v.2l.7 1.2h.4v-1.2h.2v-.2h-.2v-.4h-.3v.4z"/>
<path d="M79.9 140.1l.2-.1a.34 .34 0 0 1 .5 .2v.3l-.4 .2-.3-.3zM79.8 139.1v.2a.63 .63 0 0 1 .8 .5v.1v-.1h-.2a.4 .4 0 0 0-.5 .1l-.1 .1a.33 .33 0 0 0-.1 .5v.1a.58 .58 0 0 0 1 .1h.1a1.68 1.68 0 0 0-.1-1.3l-.3-.3z"/>
<path d="M55.5 6.8l.3 .1v.2h-.4zM54.9 6.7v.1l.4 .1v.2h-.4v.2h1v-.5l-.2-.1-.3 .1-.1 .1v-.1z"/>
<path d="M55.3 6.2h.5l-.5 .2zM54.9 6v.2h.3v.4l.7-.4v-.2h-.6v-.2h-.1v.2z"/>
<path d="M55.5 5.3l.2-.1 .1 .1v.3h-.3zM55 5.3l.3-.1v.3l-.2 .1zM55 5.2a.36 .36 0 0 0 .2 .5l.1-.1 .2 .1a.25 .25 0 0 0 .3-.1 .25 .25 0 0 0 .1-.3 .22 .22 0 0 0-.3-.1 .22 .22 0 0 0-.2 .1l-.1-.1z"/>
<path d="M81 6.8h.2v.3h-.3zM80.4 6.7v.1l.4 .1v.2h-.4v.2h.9v-.4a.22 .22 0 0 0-.2-.2 .22 .22 0 0 0-.2 .2l-.1-.1z"/>
<path d="M80.7 6.1h.5l-.5 .3zM80.4 6v.1h.2v.5l.7-.4v-.2h-.6v-.2h-.1v.2z"/>
<path d="M30.2 6.9l.2-.1 .1 .4h-.3zM29.7 6.7v.1l.4 .2v.2h-.4v.1h.9v-.3a.26 .26 0 0 0-.2-.2 .26 .26 0 0 0-.3 .1v-.1z"/>
<path d="M30 6.2h.4l-.4 .3zM29.7 6v.2h.1v.4h.2l.6-.4v-.2h-.6v-.1z"/>
<path d="M30 5.4h.4l-.4 .3zM29.7 5.2v.2h.1v.4h.2l.6-.4v-.2h-.6v-.1h-.2v.1z"/>
<path d="M71.8 66.6h.2l.2 .2-.1 .1h-.3zM71.7 66.1v.9h.4a.22 .22 0 0 0 .2-.2 .22 .22 0 0 0-.2-.2l.2-.5h-.1l-.2 .4h-.2v-.4z"/>
<path d="M73.3 66.7h.1h.3v.2h-.3zM73.3 66.2h.4v.3h-.3zM73.3 66.1v.4l.1 .1a.23 .23 0 0 0-.1 .3 .23 .23 0 0 0 .3 .1l.3-.1v-.2l-.2-.1a.22 .22 0 0 0 .2-.2 .22 .22 0 0 0-.2-.3z"/>
<path d="M56.9 117.7h.2v.2h-.2zM56.8 118.2l.3-.2v.4h-.2zM56.8 117.6l-.1 .2 .2 .2a.23 .23 0 0 0-.2 .3 .23 .23 0 0 0 .3 .1h.3v-.8z"/>
<path d="M70.5 113.2h.2v.3h-.2zM70.5 112.8h.2l.1 .1-.1 .1h-.2zM70.3 112.7v.8h.3a.22 .22 0 0 0 .2 0 .22 .22 0 0 0 0-.3l-.1-.1a.23 .23 0 0 0 .2-.3 .23 .23 0 0 0-.3-.1z"/>
<path d="M64.4 107l.1-.1h.2v.2h-.2zM64.4 107.3h.3v.2h-.3zM64.3 106.9v.2l.2 .1h-.1a.24 .24 0 0 0-.1 .3 .24 .24 0 0 0 .3 .1h.3v-.8h-.5z"/>
<path d="M45.4 122.6l.4-.1-.3 .4-.1-.2zM46 122.5v.1h.1v.1l-.1 .2h-.4zM45.3 122.6a.34 .34 0 0 0 .4 .4h.2a.32 .32 0 0 0 .3-.4 .87 .87 0 0 0-.7-.2z"/>
<path d="M50.7 132.4l.3 .1v.2v.1h-.3v-.2h-.1zM50.3 132.5l-.1 .3 .2-.2v-.1l.2-.1-.1 .2a.3 .3 0 0 0 .5 .3 .3 .3 0 0 0 0-.5l-.1-.1a.55 .55 0 0 0-.6 .2z"/>
<path d="M54.5 109.8a.21 .21 0 0 1 .4 0 .21 .21 0 0 1-.4 0zM54.4 109.6v.1a.57 .57 0 0 0 .3 .7h.2v-.1l-.4-.1v-.2l.1 .1h.2l.1-.3h.1l-.1-.1a.3 .3 0 0 0-.5-.1z"/>
<path d="M55.3 109.9l.3 .3a.18 .18 0 0 1-.2 .1 .18 .18 0 0 1-.1-.2zM55.3 109.7l.1-.1a.38 .38 0 0 1 .2 .5zM55.2 109.6l-.1 .1v.5h.1a.26 .26 0 0 0 .3 .2 .26 .26 0 0 0 .2-.2h.1v-.5h-.1a.3 .3 0 0 0-.5-.1z"/>
<path d="M80.4 102.7h.1a.19 .19 0 0 1 .3-.1 .19 .19 0 0 1 .1 .3l-.1 .1h-.3zM80.2 102.8a.38 .38 0 0 0 .2 .5v.1l.1-.1-.1-.1a.24 .24 0 0 1-.1-.2 .24 .24 0 0 1 .1-.2l.1 .3a.26 .26 0 0 0 .3 0 .26 .26 0 0 0 .2-.3 .26 .26 0 0 0-.2-.3 .26 .26 0 0 0-.3 .1z"/>
<path d="M72 107.5h.2a.21 .21 0 0 1 .2 .2 .21 .21 0 0 1-.3 .2 .21 .21 0 0 1-.1-.4zM71.9 107.5v.2a.34 .34 0 0 0 .5 .3l.4-.1v-.4l-.1 .3h-.2v.1h-.1l.1-.1-.1-.4h-.3z"/>
<path d="M43.9 108.8h.4v.5zM43.8 108.7l.4 .7h.2v-.6h.1v-.1h-.1v-.2h-.1v.2z"/>
<path d="M44.7 108.8h.3v.5zM44.6 108.7l.4 .7h.1v-.6h.2v-.1h-.2v-.2h-.1v.2z"/>
<path d="M88.9 110l.3 .4h-.3zM88.8 109.8v.6h-.2v.1h.2v.3h.1v-.3h.4v-.1l-.3-.6z"/>
<path d="M40.2 88.8l.4-.3v.3zM40.1 88.7v.2h.5v.1h.1v-.1h.3v-.1h-.3v-.4z"/>
<path d="M91.6 83.6l.3 .5h-.3zM91.4 83.5v.6h-.1h.1v.3h.2v-.3h.4l-.3-.6z"/>
<path d="M90.8 83.6a.25 .25 0 0 1 .3 .1 .25 .25 0 0 1 0 .3zM90.7 83.8l.4 .3-.1 .2a.32 .32 0 0 1-.3-.4zM90.6 83.6v.2a.38 .38 0 0 0 .2 .5 .24 .24 0 0 0 .2 .1 .24 .24 0 0 0 .2-.3 .45 .45 0 0 0-.3-.6h-.1z"/>
<path d="M77.6 129.2l.4-.4a.25 .25 0 0 1 0 .3 .25 .25 0 0 1-.3 .1zM77.3 128.9l.2-.2h.2l-.2 .5-.2-.1zM77.3 128.7v.1a.24 .24 0 0 0-.1 .3 .24 .24 0 0 0 .3 .2h.1a.39 .39 0 0 0 .4-.1 .39 .39 0 0 0 .2-.4h-.1a.44 .44 0 0 0-.6-.1z"/>
<path d="M45.7 33.1h.4v.1a.18 .18 0 0 1-.3 .2 .18 .18 0 0 1-.1-.3zM45.7 33.6l.3-.1 .1 .3h-.4zM45.6 33v.4l.2 .1-.3 .1v.2l.3 .1v.1l.3-.1a.17 .17 0 0 0 .1-.2 .17 .17 0 0 0-.1-.2h-.1a.24 .24 0 0 0 .1-.2 .24 .24 0 0 0 0-.3z"/>
<path d="M75.1 33.1l.4 .5h-.4zM75 33v.6h-.1v.1h.1v.2h.1v-.2h.5l-.4-.7z"/>
<path d="M92.8 90.1h.2v.1h-.2zM92.7 89.7v.6h.2v-.1h.1v-.1l-.1-.1h.1v-.3l-.1 .3h-.1v-.3z"/>
<path d="M93.2 89.9h.2v.3zM93.1 89.9l.3 .4h.1v-.4v-.2h-.1v.2z"/>
<path d="M92.8 98l.2 .2h-.2zM92.7 97.7v.6h.3v-.2l-.1-.1h.1v-.3l-.1 .2z"/>
<path d="M93.2 97.9h.2v.3zM93.1 97.8l.3 .5h.1v-.4v-.1v-.1l-.1 .1z"/>
<path d="M84.6 100.7h.2v.2h-.2zM84.5 100.4v.6h.3v-.1v-.3l.1-.2h-.1v.2h-.2v-.2z"/>
<path d="M85 100.5h.2v.4zM84.9 100.5l.3 .5h.1v-.5v-.1h-.1v.1z"/>
<path d="M92.8 92.7l.2 .1h-.2zM92.7 92.4v.5h.3v-.1l-.1-.1h.1v-.3l-.2 .3v-.3z"/>
<path d="M93.2 92.6h.2v.2zM93.1 92.5l.2 .4h.2v-.3v-.1v-.1l-.1 .1z"/>
<path d="M93.6 92.6l.3 .2h-.3zM93.7 92.4l.2 .1v.2zM93.6 92.4l-.1 .3 .1 .1a.21 .21 0 0 0 .3 .1 .21 .21 0 0 0 .1-.3v-.2z"/>
<path d="M92.8 100.7h.2v.1l-.2 .1zM92.7 100.4v.6h.2v-.1h.1v-.2l-.1-.1h.1v-.2l-.1 .2h-.1v-.2z"/>
<path d="M93.7 100.6h.2v.3h-.2zM93.6 100.4h.3v.2h-.3v.2a.18 .18 0 0 0 .2 .1 .18 .18 0 0 0 .2-.2v-.2l-.2-.1z"/>
<path d="M92.8 95.4h.2v.1h-.2zM92.7 95v.6h.2v-.1h.1v-.1l-.1-.1h.1v-.3l-.1 .3h-.1v-.3z"/>
<path d="M93.7 95.4h.2v.1h-.2zM93.7 95.1h.2v.2h-.2zM93.6 95v.3h.1l-.1 .2a.18 .18 0 0 0 .2 .1 .18 .18 0 0 0 .2-.2h-.1l.1-.3-.1-.1z"/>
<path d="M68.7 87h.2v.2h-.2zM68.6 86.8v.5h.4v-.3l-.1-.1 .1-.1-.2 .2h-.1v-.2z"/>
<path d="M68.7 92.8h.2v.1h-.2zM68.6 92.5v.5h.4v-.2l-.1-.1 .1-.2-.1 .2h-.2v-.2z"/>
<path d="M69.7 92.5l.2 .1-.1 .2h-.2zM69.5 92.6v.2l.2 .2h.2v-.1h-.2l-.1-.1h.2l.2-.1a.24 .24 0 0 0-.2-.2 .24 .24 0 0 0-.3 .1z"/>
<path d="M68.7 84.6h.2v.2h-.2zM68.6 84.3v.6h.3l.1-.1-.1-.2 .1-.3-.2 .3h-.1v-.3z"/>
<path d="M69.6 84.5h.2v.3zM69.5 84.5l.2 .4h.2v-.4h.1h-.1v-.2h-.1v.2z"/>
<path d="M84.7 87.4h.1v.1h-.1zM84.6 87.1v.5h.3v-.2l-.1-.1 .2-.2-.2 .3h-.1v-.3z"/>
<path d="M76.6 84.7h.2v.2h-.2zM76.6 84.4v.6h.1v-.1h.2v-.2l-.2-.1h.1l.1-.2h-.1l-.1 .2h-.1v-.2z"/>
<path d="M92.8 103.3l.2 .2h-.2zM92.7 103.1v.5h.3v-.2l-.1-.1h.1v-.2l-.1 .1z"/>
<path d="M93.6 103.2l.3 .3-.3-.1zM93.7 103.1h.2v.2zM93.6 103.1l-.1 .2h.1v.3h.2a.38 .38 0 0 0 .2-.5z"/>
<path d="M76.6 87.4h.2v.1h-.2zM76.6 87.1v.5h.2l.1-.2h-.2h.1l.1-.3-.2 .2z"/>
<path d="M77.6 87.4h.1v.1h-.1zM77.5 87.1h.2v.2a.19 .19 0 0 0-.2 .1 .19 .19 0 0 0 .1 .2h.1a.27 .27 0 0 0 .1-.3 .27 .27 0 0 0-.3-.2z"/>
<path d="M76.6 95.2h.2v.2h-.2zM76.6 94.9v.6h.1l.2-.1v-.2l-.2-.1h.1l.1-.2h-.1l-.1 .2h-.1v-.2z"/>
<path d="M77.6 95.2h.1v.2h-.1zM77.6 95h.1v.1h-.1zM77.5 94.9v.2h.1l-.1 .2a.18 .18 0 0 0 .2 .2 .18 .18 0 0 0 .1-.3h-.1l.1-.1-.1-.2z"/>
<path d="M76.6 92.7l.2 .1h-.2zM76.6 92.4v.5h.2l.1-.1-.2-.1h.1l.1-.3-.3 .3v-.3z"/>
<path d="M77.6 92.4h.1v.3h-.1zM77.5 92.4a.34 .34 0 0 0 .2 .5l.1-.1h-.2v-.1v.1h.1l.1-.1v-.3z"/>
<path d="M76.6 90.1h.2v.1h-.2zM76.6 89.7v.6h.1l.2-.1v-.1l-.2-.1h.1l.1-.3h-.1l-.1 .3h-.1v-.3z"/>
<path d="M84.7 95.4h.1v.1h-.1zM84.6 95v.6h.2v-.1h.1l-.1-.3 .2-.2-.2 .3h-.1v-.3z"/>
<path d="M85.6 95.2h.2v.3zM85.5 95.2l.2 .4h.2v-.4v-.2h-.1v.2z"/>
<path d="M84.7 90.1h.1v.1h-.1zM84.6 89.7v.6h.2l.1-.1v-.2h-.1h.1l.1-.3h-.1l-.1 .3h-.1v-.3z"/>
<path d="M84.7 84.7h.1v.2h-.1zM84.6 84.4v.6h.2l.1-.1v-.3h-.1h.1l.1-.2h-.1l-.1 .2h-.1v-.2z"/>
<path d="M84.7 92.7h.1v.1h-.1zM84.6 92.4v.5h.3v-.2l-.1-.1 .2-.2-.2 .2h-.1v-.2z"/>
<path d="M84.7 98h.1v.2h-.1zM84.6 97.7v.6h.3v-.3l-.1-.1 .2-.2-.2 .2h-.1v-.2z"/>
<path d="M85.6 97.9l.3 .2-.3 .1zM85.6 97.8l.2-.1 .1 .3zM85.5 97.8v.3a.22 .22 0 0 0 .3 .2 .22 .22 0 0 0 .1-.3v-.3h-.3z"/>
<path d="M70.7 97h.2v.2h-.2zM70.4 96.8v.1l.2 .1v.2h-.2h.6v-.3h-.3l-.1 .1v-.1z"/>
<path d="M70.7 96l.2 .1v.1h-.2zM70.5 96v.2l-.1 .1h.1v-.2l.1-.1v.1a.18 .18 0 0 0 .3 .2 .18 .18 0 0 0 .1-.2v-.1z"/>
<path d="M78.2 109.4h.2v.2h-.2zM78.2 109.3v.3v.1h.2v-.1l.3 .1-.2-.2 .2-.2z"/>
<path d="M81 109.5h.2v.2zM81 109.4v.3h.1l.2-.1v.1h.2l-.2-.1v-.1h.2v-.1z"/>
<path d="M81 110.5l.4-.2v.2zM81 110.5v.1h.4v.1l.1-.1v-.1v-.3z"/>
<path d="M28.4 115.9h.2v.2h-.2zM28.3 115.9l.1 .3h-.1l-.1 .2h.1l.1-.2h.2v.2v-.6z"/>
<path d="M87.1 123.3h.2v.2h-.2zM86.8 123.3l.2 .1v.1h-.2v.1h.6v-.3h-.1h-.2z"/>
<path d="M87.1 118.8h.2v.1h-.2zM86.8 118.7v.1l.2 .1h-.2v.1h.6v-.2l-.1-.1h-.2v.1z"/>
<path d="M87 118.4h.3l-.3 .1zM86.8 118.3v.1h.2v.2l.4-.2v-.1h-.4v-.1z"/>
<path d="M82.8 121.7h.2v.2h-.2zM82.7 121.7v.2h.1l-.1 .3h.1l.1-.2h.1v.2h.1v-.5z"/>
<path d="M84.2 115.4l.1 .1v.2h-.1zM83.8 115.3v.1l.3 .1v.2h-.3h.5v-.3h-.2v.1v-.1z"/>
<path d="M51.8 120.6l.2-.1 .1 .2h-.3zM51.5 120.6v.1h.1v-.1l.2-.1v.3h.2a.18 .18 0 0 0 .1-.2 .18 .18 0 0 0-.2-.1l-.1-.1v.1z"/>
<path d="M51.6 121h.2v.1h-.2zM51.5 121a.28 .28 0 0 0 .2 .2 .28 .28 0 0 0 .4-.1v-.2l-.1 .2h-.1v-.2h-.3z"/>
<path d="M48.8 117.6l.3 .1h-.1v.1h-.2zM48.6 117.6v.2l.1-.2h.1a.19 .19 0 0 0 0 .2 .19 .19 0 0 0 .3 0v-.1a.3 .3 0 0 0-.5-.1z"/>
<path d="M48.6 118.1h.2v.2h-.2zM48.8 118.1l.2-.1v.3zM48.6 118v.4h.2v-.1v.1a.19 .19 0 0 0 .3-.1 .19 .19 0 0 0-.1-.3h-.2v.1v-.1z"/>
<path d="M55.8 130l.1-.1 .1 .2-.2 .1zM55.7 130v.1a.31 .31 0 0 0 .4 .2 .31 .31 0 0 0 .2-.4h-.1l-.1 .3h-.1v-.3l-.1-.1z"/>
<path d="M44.2 132.5h.2v.1v.1l-.2-.1zM44.2 132.4v.1h-.1a.38 .38 0 0 0 .5 .2l.1-.1v-.2h-.1v.2l-.2 .1v-.3z"/>
<path d="M44.2 132h.2v.2h-.2zM44.1 132l.1 .3h.3l.2-.2v-.1h-.1v.2h-.2v-.2v-.1z"/>
<path d="M65.1 112h.1v.3h-.1zM65 111.8v.1h.2v.1v-.1l-.2 .1a.19 .19 0 0 0 .1 .3 .19 .19 0 0 0 .2-.1v-.3l-.1-.1z"/>
<path d="M64.6 111.9l.2 .2h-.2zM64.6 111.8v.3l-.1 .1 .1 .1v-.1h.3l-.3-.4z"/>
<path d="M67.9 99.1l.1-.1v.1h.2v.2h-.3zM67.7 99.1v.2h.1v-.2h.1v-.1v.3a.22 .22 0 0 0 .3 0 .22 .22 0 0 0 0-.3h-.4z"/>
<path d="M57.4 104.7h.1v.1h-.1zM57.1 104.7v.2l.1-.2h.2h-.1l.1 .2 .2-.1v-.2h-.4z"/>
<path d="M74.5 100.5h.2v.3h-.2zM74.4 100.3v.1h.3v.1h-.3v.2a.18 .18 0 0 0 .3 .2 .18 .18 0 0 0 .1-.3v-.2z"/>
<path d="M60 107.7l.3-.2v.2zM60 107.7v.1h.3v.1l.2-.1-.1-.1v-.2z"/>
<path d="M66.5 89.9h.2v.2zM66.4 89.8l.3 .4h.1v-.3v-.1v-.1l-.1 .1z"/>
<path d="M67 90.1l.1-.1 .1 .1-.1 .1zM67 89.7h.2l-.1 .3zM66.9 89.7v.2h.1l-.1 .2a.19 .19 0 0 0 .3 .1 .19 .19 0 0 0 .1-.2h-.1h.1v-.3z"/>
<path d="M63.8 93.9h.3l-.1 .2zM63.7 93.9l.3 .2-.1 .2 .2-.1v-.1l.1-.2z"/>
<path d="M46.5 96.8l.3-.2v.2zM46.5 96.7v.1h.3v.1l.2-.1h-.1v-.3z"/>
<path d="M46.7 97.1h.2v.2h-.2zM46.5 97.1v.2l.1-.2v.1a.18 .18 0 0 0 .3 .2 .18 .18 0 0 0 .1-.2l-.2-.2z"/>
<path d="M79.9 97.9h.2v.3zM79.9 97.8l.1 .5h.2v-.4l.1-.1-.1-.1-.1 .1z"/>
<path d="M48.4 87.3h.3v.1h-.3zM48.4 87l.3 .1v.2v-.1h-.2a.18 .18 0 0 0-.2 .2 .18 .18 0 0 0 .3 .1 .27 .27 0 0 0 .2-.3 .27 .27 0 0 0-.4-.2z"/>
<path d="M52.1 101.4l.2 .1-.1 .1zM51.9 101.4l.2 .1-.1 .1h-.1zM51.8 101.4v.2l.1 .1 .2-.2 .1 .2 .2-.2-.1-.2-.2 .2-.1-.2z"/>
<path d="M81.1 90.6l.2 .1v.2l-.3-.1zM81 90.7v.1a.22 .22 0 0 0 .2 .2 .22 .22 0 0 0 .3-.2v-.2l-.2 .3a.18 .18 0 0 0 0-.3 .18 .18 0 0 0-.3 0z"/>
<path d="M69.5 127.1h.3v.4zM69.5 127.1l.2 .5h.2v-.5h.1h-.1v-.1h-.1v.1z"/>
<path d="M63 33.7h.1v.3zM62.9 33.6l.2 .4h.1v-.3l.1-.1-.1-.1-.1 .1z"/>
<path d="M51.5 66.1l.1 .1v.2zM51.4 66.3l.2 .3h-.1zM51.4 66.1l-.1 .4h.1v.2h.1a.38 .38 0 0 0 .2-.6z"/>
<path d="M80.7 33.6l.2-.1v.2h.1l-.3 .1zM80.6 33.6v.4h.1h.3h-.3v-.2v.1a.19 .19 0 0 0 .3-.1 .19 .19 0 0 0-.1-.3z"/>
<path d="M96 36.9l.2-.1v.2h-.2zM95.7 36.7v.1l.3 .1v.1h-.3v.1h.5v-.3v-.1l-.2 .2v-.1z"/>
<path d="M96 35.9h.2v.2h-.2zM95.7 35.9v.3l.1-.3h.2h-.1l.1 .3a.19 .19 0 0 0 .2-.1 .19 .19 0 0 0 0-.3h-.4z"/>
<path d="M101.5 36.9a1.23 1.23 0 0 1 1.3 0v.3a.46 .46 0 0 1-.6 .4 .6 .6 0 0 1-.8-.5h.1zM100.8 36.4v.2h-.1a.6 .6 0 0 0 .3 .7h.2a.59 .59 0 0 0 .6 .5 1.1 1.1 0 0 0 1.1-.2l.1-.2a.68 .68 0 0 0-.6-.9h-.7v.1l-.3 .1-.1 .2h-.1v.2a.33 .33 0 0 1-.2-.3 .33 .33 0 0 1 .1-.3z"/>
<path d="M100.1 42.2h.2v.2h-.2zM100.1 42.2v.2v.3l.1-.2h.1v.2h.1v-.5z"/>
<path d="M99.6 42.5l.2-.1 .1 .2-.3 .1zM99.6 42.2l.3 .2h-.4v.2a.17 .17 0 0 0 .2 .1 .17 .17 0 0 0 .2-.1h.1l-.1-.4z"/>
</g>
<path d="M6.5 31.3a1.33 1.33 0 0 0-1.3 1.4M20.4 31.3a1.33 1.33 0 0 1 1.3 1.4M113 31.3a1.33 1.33 0 0 0-1.4 1.4M126.9 31.3a1.33 1.33 0 0 1 1.3 1.4M5.2 133.9a1.33 1.33 0 0 0 1.3 1.4M21.7 133.9a1.33 1.33 0 0 1-1.3 1.4M111.6 133.9a1.33 1.33 0 0 0 1.4 1.4M128.2 133.9a1.33 1.33 0 0 1-1.3 1.4M32.7 144.9a1.33 1.33 0 0 0-1.4 1.3M100.7 144.9a1.33 1.33 0 0 1 1.3 1.3M31.3 160.1a1.33 1.33 0 0 0 1.4 1.3M102 160.1a1.33 1.33 0 0 1-1.3 1.3" fill="none" stroke="#5a5a5a" stroke-width=".42"/>
<path d="M.1 .2h133.1v166.3h-133.1z" fill="none" stroke="#5a5a5a" stroke-width=".33"/>
</svg>
